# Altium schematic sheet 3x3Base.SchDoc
size A3; SheetNumber: 1; SheetTotal: 1

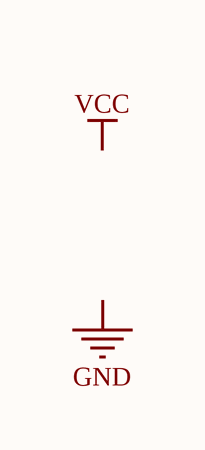
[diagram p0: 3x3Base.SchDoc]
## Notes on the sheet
- Labels drawn without touching a wire or pin: GND, VCC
